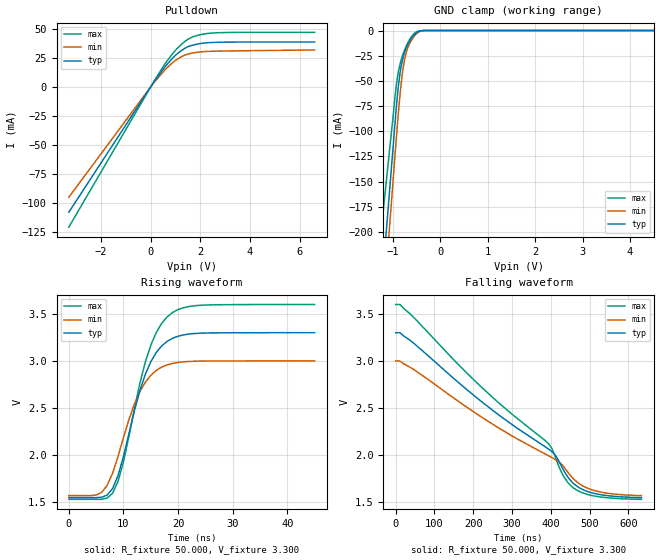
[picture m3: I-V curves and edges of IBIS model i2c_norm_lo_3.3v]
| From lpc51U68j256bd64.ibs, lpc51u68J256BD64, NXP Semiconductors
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[Model]   i2c_norm_lo_3.3v
Model_type I/O_open_drain
Vinl=8.000E-01
Vinh=2.000E+00
Vref=3.300E+00
Rref=1.000E+03
Cref=0.000E+00
Vmeas=1.650E+00
C_comp   1.270E-12   1.260E-12   1.280E-12
[Voltage Range]   3.300E+00   3.000E+00   3.600E+00
[POWER Clamp Reference]   3.300E+00   3.000E+00   3.600E+00
[GND Clamp Reference]   0.000E+00   0.000E+00   0.000E+00
[Pullup Reference]   3.300E+00   3.000E+00   3.600E+00
[Pulldown Reference]   0.000E+00   0.000E+00   0.000E+00
[Temperature Range]   25   105   -40
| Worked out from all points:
|   slope of the pulldown table from 0 to 0.495 V, typ, clamps not added: 33 ohm
|   GND clamp passes 1 mA (typ) near -0.46 V on its own axis
|   rising waveform, R_fixture 50.000, V_fixture 3.300: 20-80 % time 5.12ns typ, 5.13ns min, 5.08ns max; typ from 1.55 V to 3.3 V
|   falling waveform, R_fixture 50.000, V_fixture 3.300: 20-80 % time 313ns typ, 324ns min, 305ns max; typ from 3.3 V to 1.55 V
[GND Clamp]
-3.3V     -1.458A    -1.562A    -1.131A
-1.02V    -130mA     -163.9mA   -96.03mA
-940mV    -83.07mA   -114.7mA   -59.17mA
-880mV    -53.59mA   -79.56mA   -39.94mA
-820mV    -34.18mA   -50.5mA    -28.4mA
-780mV    -25.98mA   -36.17mA   -22.72mA
-720mV    -17.58mA   -22.11mA   -15.62mA
-660mV    -11.67mA   -14.14mA   -9.957mA
-560mV    -4.68mA    -6.191mA   -3.364mA
-480mV    -1.522mA   -2.335mA   -915uA
-340mV    0A         0A         0A
6.6V      0A         0A         0A
[Pulldown]
-3.3V     -108.3mA   -95.33mA   -121.2mA
160mV     5.143mA    4.418mA    5.829mA
580mV     17.51mA    14.82mA    20.06mA
840mV     23.85mA    20.1mA     27.52mA
1.04V     28.06mA    23.49mA    32.6mA
1.36V     33.07mA    27.32mA    38.93mA
1.68V     35.86mA    29.22mA    43.1mA
1.9V      37.05mA    29.92mA    44.55mA
2.58V     38.42mA    30.76mA    46.6mA
6.6V      38.69mA    31.86mA    47.08mA
[Rising Waveform]
R_fixture = 50.000
V_fixture = 3.300
V_fixture_min = 3.000
V_fixture_max = 3.600
|  time   V(typ)   V(min)   V(max)
0s        1.546V     1.568V     1.528V
6ns       1.55V      1.602V     1.528V
8ns       1.641V     1.804V     1.592V
10ns      1.982V     2.183V     1.924V
12ns      2.467V     2.54V      2.488V
15ns      2.99V      2.846V     3.166V
17ns      3.159V     2.934V     3.4V
19ns      3.241V     2.974V     3.515V
24ns      3.295V     2.998V     3.591V
45ns      3.3V       3V         3.6V
[Falling Waveform]
R_fixture = 50.000
V_fixture = 3.300
V_fixture_min = 3.000
V_fixture_max = 3.600
|  time   V(typ)   V(min)   V(max)
0s        3.3V       3V         3.6V
12ns      3.297V     2.995V     3.596V
44ns      3.197V     2.915V     3.473V
244ns     2.495V     2.343V     2.635V
393ns     2.066V     1.995V     2.124V
415ns     1.978V     1.943V     1.943V
432ns     1.846V     1.881V     1.78V
457ns     1.703V     1.753V     1.655V
515ns     1.589V     1.619V     1.562V
634ns     1.546V     1.568V     1.528V
[Ramp]
dV/dt_r   1.0522E+00/5.0520E-09   8.5491E-01/5.0710E-09   1.2498E+00/5.0520E-09
dV/dt_f   1.0522E+00/3.1298E-07   8.5491E-01/3.2391E-07   1.2498E+00/3.0505E-07
R_load = 50
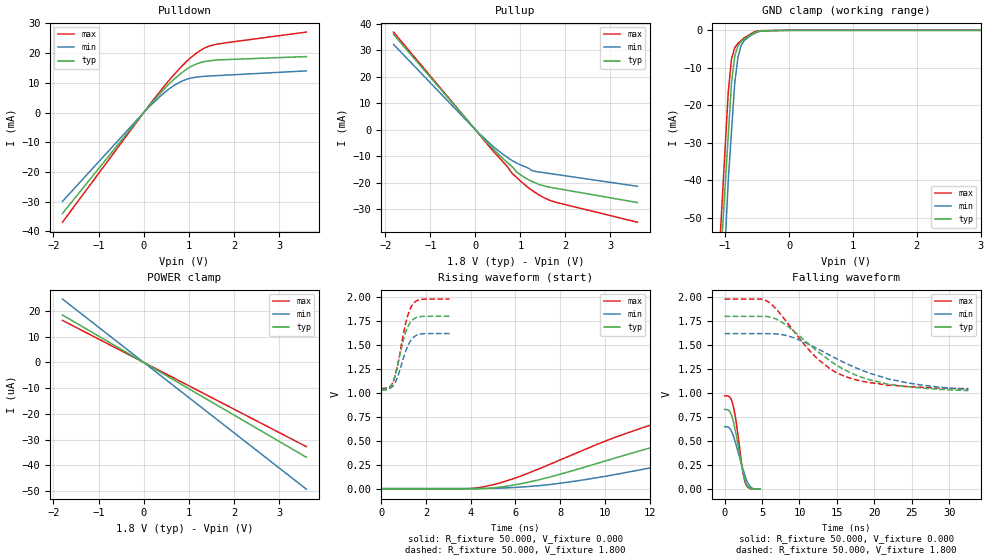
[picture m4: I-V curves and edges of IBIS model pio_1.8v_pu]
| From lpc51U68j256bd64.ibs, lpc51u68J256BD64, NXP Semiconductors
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[Model]   pio_1.8v_pu
Model_type I/O
Vinl=4.000E-01
Vinh=1.500E+00
Vref=0.000E+00
Rref=1.000E+06
Cref=2.000E-11
Vmeas=9.000E-01
C_comp   9.060E-12   8.700E-12   9.420E-12
[Voltage Range]   1.800E+00   1.620E+00   1.980E+00
[POWER Clamp Reference]   1.800E+00   1.620E+00   1.980E+00
[GND Clamp Reference]   0.000E+00   0.000E+00   0.000E+00
[Pullup Reference]   1.800E+00   1.620E+00   1.980E+00
[Pulldown Reference]   0.000E+00   0.000E+00   0.000E+00
[Temperature Range]   25   105   -40
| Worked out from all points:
|   slope of the pulldown table from 0 to 0.27 V, typ, clamps not added: 55.9 ohm
|   slope of the pullup table from 0 to 0.27 V, typ, clamps not added: 53.5 ohm
|   GND clamp passes 1 mA (typ) near -0.59 V on its own axis
|   rising waveform, R_fixture 50.000, V_fixture 0.000: 20-80 % time 8.49ns typ, 10.2ns min, 6.96ns max; typ from -0.006 V to 0.824 V
|   falling waveform, R_fixture 50.000, V_fixture 0.000: 20-80 % time 1.2ns typ, 1.45ns min, 1.03ns max; typ from 0.831 V to 0.001 V
|   rising waveform, R_fixture 50.000, V_fixture 1.800: 20-80 % time 492ps typ, 502ps min, 486ps max; typ from 1.03 V to 1.8 V
|   falling waveform, R_fixture 50.000, V_fixture 1.800: 20-80 % time 8.49ns typ, 10.1ns min, 6.71ns max; typ from 1.8 V to 1.03 V
[GND Clamp]
-1.8V     -263.7mA   -335.6mA   -275.8mA
-950mV    -27.75mA   -39.74mA   -16.17mA
-900mV    -13.87mA   -26.94mA   -7.61mA
-850mV    -6.971mA   -14.14mA   -4.632mA
-800mV    -4.156mA   -7.28mA    -3.484mA
-750mV    -2.988mA   -4.044mA   -2.731mA
-700mV    -2.361mA   -2.687mA   -1.978mA
-600mV    -1.106mA   -1.378mA   -966uA
-550mV    -718uA     -946.2uA   -460.3uA
-450mV    -144.5uA   -255.5uA   -88.61uA
0V        0A         0A         0A
3.6V      0A         0A         0A
[Power Clamp]
-1.8V     18.45uA    24.66uA    16.39uA
0V        0A         0A         0A
3.6V      -36.9uA    -49.32uA   -32.77uA
[Pullup]
-1.82V    35.96mA    32.21mA    36.85mA
80mV      -1.544mA   -1.344mA   -1.647mA
500mV     -9.045mA   -7.794mA   -9.994mA
700mV     -12.23mA   -10.32mA   -13.77mA
800mV     -13.69mA   -11.44mA   -16.11mA
940mV     -16.27mA   -12.77mA   -18.38mA
1.16V     -18.65mA   -14.36mA   -21.65mA
1.26V     -19.53mA   -15.44mA   -22.89mA
1.44V     -20.77mA   -16.02mA   -24.89mA
1.66V     -21.72mA   -16.55mA   -26.68mA
3.6V      -27.48mA   -21.34mA   -34.89mA
[Pulldown]
-1.8V     -34.01mA   -29.94mA   -36.95mA
0V        0A         0A         0A
380mV     6.716mA    5.665mA    7.485mA
600mV     10.22mA    8.397mA    11.57mA
840mV     13.38mA    10.54mA    15.59mA
1.02V     15.31mA    11.52mA    18.23mA
1.16V     16.32mA    11.92mA    19.92mA
1.38V     17.25mA    12.23mA    21.97mA
1.62V     17.72mA    12.43mA    23.02mA
3.6V      18.85mA    14.03mA    27.1mA
[Rising Waveform]
R_fixture = 50.000
V_fixture = 0.000
V_fixture_min = 0.000
V_fixture_max = 0.000
|  time   V(typ)   V(min)   V(max)
0s        -5.789mV   1.396mV    -4.844mV
3.7ns     -4.923mV   1.575mV    -2.372mV
4.95ns    6.383mV    3.245mV    37.73mV
7.05ns    91.82mV    30.65mV    206.2mV
11.75ns   407.3mV    203.7mV    641.5mV
13.6ns    519.6mV    286.3mV    761.3mV
15.5ns    613.2mV    365.4mV    841.4mV
20.9ns    764.1mV    538mV      935mV
25.8ns    810.2mV    622mV      959mV
30.1ns    823.9mV    651.5mV    967.2mV
[Falling Waveform]
R_fixture = 50.000
V_fixture = 0.000
V_fixture_min = 0.000
V_fixture_max = 0.000
|  time   V(typ)   V(min)   V(max)
0s        831.3mV    651.5mV    972.6mV
650ps     813mV      636.2mV    961.7mV
900ps     776.3mV    607.1mV    932mV
1.15ns    713.4mV    560.6mV    870.8mV
1.6ns     547.3mV    446.3mV    673.2mV
2.4ns     201.9mV    225.1mV    202.4mV
2.8ns     76.49mV    124.4mV    60.41mV
3.1ns     29.6mV     66.64mV    21.01mV
3.55ns    6.817mV    18.78mV    4.66mV
4.75ns    1.009mV    1.396mV    965.5uV
[Rising Waveform]
R_fixture = 50.000
V_fixture = 1.800
V_fixture_min = 1.620
V_fixture_max = 1.980
|  time   V(typ)   V(min)   V(max)
0s        1.028V     1.04V      1.048V
350ps     1.047V     1.046V     1.059V
550ps     1.131V     1.081V     1.128V
700ps     1.257V     1.15V      1.256V
1.05ns    1.603V     1.408V     1.686V
1.2ns     1.697V     1.498V     1.821V
1.4ns     1.764V     1.571V     1.924V
1.55ns    1.786V     1.598V     1.958V
1.75ns    1.797V     1.614V     1.975V
3.05ns    1.8V       1.62V      1.98V
[Falling Waveform]
R_fixture = 50.000
V_fixture = 1.800
V_fixture_min = 1.620
V_fixture_max = 1.980
|  time   V(typ)   V(min)   V(max)
0s        1.8V       1.62V      1.98V
4.75ns    1.8V       1.62V      1.98V
5.8ns     1.797V     1.619V     1.952V
8.15ns    1.713V     1.602V     1.756V
12.3ns    1.442V     1.468V     1.366V
14.15ns   1.333V     1.391V     1.25V
16.25ns   1.234V     1.309V     1.17V
21.75ns   1.095V     1.151V     1.083V
26.55ns   1.052V     1.082V     1.061V
32.55ns   1.028V     1.04V      1.048V
[Ramp]
dV/dt_r   4.9781E-01/8.4744E-09   3.9098E-01/1.0185E-08   5.8325E-01/6.9452E-09
dV/dt_f   4.6327E-01/8.4811E-09   3.4800E-01/1.0136E-08   5.5946E-01/6.7072E-09
R_load = 50
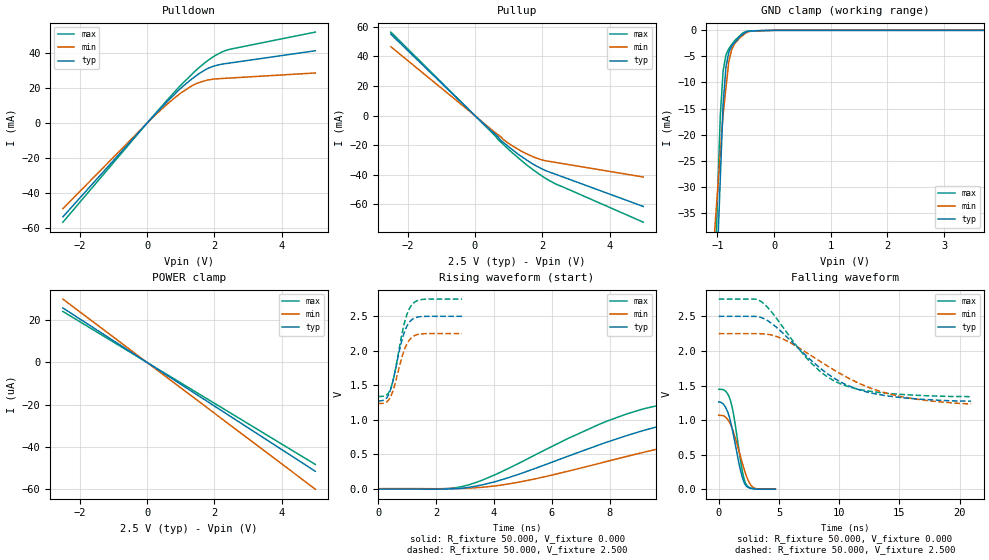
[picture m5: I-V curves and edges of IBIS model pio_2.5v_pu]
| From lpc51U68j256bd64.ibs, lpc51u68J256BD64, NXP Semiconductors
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[Model]   pio_2.5v_pu
Model_type I/O
Vinl=4.000E-01
Vinh=1.500E+00
Vref=0.000E+00
Rref=1.000E+06
Cref=2.000E-11
Vmeas=1.250E+00
C_comp   9.060E-12   8.700E-12   9.420E-12
[Voltage Range]   2.500E+00   2.250E+00   2.750E+00
[POWER Clamp Reference]   2.500E+00   2.250E+00   2.750E+00
[GND Clamp Reference]   0.000E+00   0.000E+00   0.000E+00
[Pullup Reference]   2.500E+00   2.250E+00   2.750E+00
[Pulldown Reference]   0.000E+00   0.000E+00   0.000E+00
[Temperature Range]   25   105   -40
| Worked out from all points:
|   slope of the pulldown table from 0 to 0.375 V, typ, clamps not added: 48.2 ohm
|   slope of the pullup table from 0 to 0.375 V, typ, clamps not added: 47.2 ohm
|   GND clamp passes 1 mA (typ) near -0.58 V on its own axis
|   rising waveform, R_fixture 50.000, V_fixture 0.000: 20-80 % time 5.59ns typ, 6.98ns min, 4.66ns max; typ from -0.006 V to 1.26 V
|   falling waveform, R_fixture 50.000, V_fixture 0.000: 20-80 % time 902ps typ, 1.09ns min, 781ps max; typ from 1.26 V to 0.001 V
|   rising waveform, R_fixture 50.000, V_fixture 2.500: 20-80 % time 408ps typ, 413ps min, 407ps max; typ from 1.27 V to 2.5 V
|   falling waveform, R_fixture 50.000, V_fixture 2.500: 20-80 % time 5.14ns typ, 6.37ns min, 4.26ns max; typ from 2.5 V to 1.27 V
[GND Clamp]
-2.5V     -475.7mA   -255.8mA   -509.6mA
-950mV    -28.56mA   -23.6mA    -16.48mA
-900mV    -14.13mA   -16.11mA   -7.789mA
-850mV    -7.08mA    -11.07mA   -4.709mA
-800mV    -4.224mA   -6.027mA   -3.542mA
-750mV    -3.043mA   -3.75mA    -2.78mA
-700mV    -2.406mA   -2.615mA   -2.018mA
-600mV    -1.132mA   -1.373mA   -993uA
-500mV    -345.9uA   -523.1uA   -221.8uA
-400mV    -135.5uA   -126.9uA   -93.31uA
0V        0A         0A         0A
5V        0A         0A         0A
[Power Clamp]
-2.5V     25.73uA    29.96uA    24.11uA
0V        0A         0A         0A
5V        -51.47uA   -59.93uA   -48.22uA
[Pullup]
-2.5V     55.03mA    46.51mA    56.39mA
0V        0A         0A         0A
560mV     -11.71mA   -10.66mA   -12.69mA
760mV     -16.48mA   -14.18mA   -17.72mA
1V        -20.97mA   -18.73mA   -22.83mA
1.42V     -28.23mA   -24.51mA   -31.07mA
1.96V     -35.62mA   -29.68mA   -40.25mA
2.38V     -39.45mA   -31.53mA   -45.93mA
5V        -61.32mA   -41.44mA   -71.95mA
[Pulldown]
-2.5V     -53.75mA   -49.06mA   -56.82mA
0V        0A         0A         0A
360mV     7.48mA     6.68mA     7.998mA
980mV     19.59mA    16.96mA    21.32mA
1.32V     25.16mA    21.25mA    27.81mA
1.54V     28.36mA    23.25mA    31.74mA
1.94V     32.45mA    25.18mA    37.76mA
2.36V     34.22mA    25.76mA    41.85mA
5V        41.54mA    28.79mA    52.24mA
[Rising Waveform]
R_fixture = 50.000
V_fixture = 0.000
V_fixture_min = 0.000
V_fixture_max = 0.000
|  time   V(typ)   V(min)   V(max)
0s        -5.765mV   1.234mV    -1.766mV
2.3ns     -4.275mV   975.2uV    -144.2uV
3.15ns    20.28mV    8.635mV    58.7mV
5ns       229.5mV    106.2mV    397.3mV
7.9ns     674.2mV    394.7mV    977.9mV
9.15ns    841.3mV    524.9mV    1.155V
10.4ns    976.6mV    646.1mV    1.265V
12.45ns   1.114V     811.6mV    1.354V
15.5ns    1.201V     959.5mV    1.409V
22.85ns   1.256V     1.07V      1.441V
[Falling Waveform]
R_fixture = 50.000
V_fixture = 0.000
V_fixture_min = 0.000
V_fixture_max = 0.000
|  time   V(typ)   V(min)   V(max)
0s        1.263V     1.07V      1.445V
550ps     1.19V      1.044V     1.421V
1ns       963.2mV    928.6mV    1.266V
1.3ns     715.9mV    783.8mV    1.011V
1.85ns    242.3mV    445.6mV    370.9mV
2.1ns     103.6mV    294.8mV    154.3mV
2.3ns     45.62mV    190.5mV    65.39mV
2.6ns     15.81mV    77.74mV    22.4mV
2.95ns    5.503mV    18.61mV    9.325mV
4.7ns     1.266mV    1.234mV    1.248mV
[Rising Waveform]
R_fixture = 50.000
V_fixture = 2.500
V_fixture_min = 2.250
V_fixture_max = 2.750
|  time   V(typ)   V(min)   V(max)
0s        1.274V     1.235V     1.337V
250ps     1.298V     1.248V     1.349V
350ps     1.353V     1.28V      1.385V
450ps     1.465V     1.352V     1.475V
600ps     1.734V     1.549V     1.738V
850ps     2.199V     1.947V     2.302V
1ns       2.363V     2.105V     2.534V
1.2ns     2.461V     2.206V     2.684V
1.55ns    2.498V     2.247V     2.745V
2.9ns     2.5V       2.25V      2.75V
[Falling Waveform]
R_fixture = 50.000
V_fixture = 2.500
V_fixture_min = 2.250
V_fixture_max = 2.750
|  time   V(typ)   V(min)   V(max)
0s        2.5V       2.25V      2.75V
2.95ns    2.499V     2.25V      2.749V
3.55ns    2.481V     2.248V     2.71V
5.25ns    2.27V      2.178V     2.363V
7.7ns     1.859V     1.929V     1.82V
8.95ns    1.68V      1.79V      1.634V
10.25ns   1.539V     1.655V     1.515V
12.25ns   1.409V     1.486V     1.425V
14.65ns   1.335V     1.357V     1.377V
20.95ns   1.274V     1.235V     1.337V
[Ramp]
dV/dt_r   7.5711E-01/5.5865E-09   6.3920E-01/6.9663E-09   8.6573E-01/4.6619E-09
dV/dt_f   7.3584E-01/5.1385E-09   6.0892E-01/6.3638E-09   8.4764E-01/4.2601E-09
R_load = 50
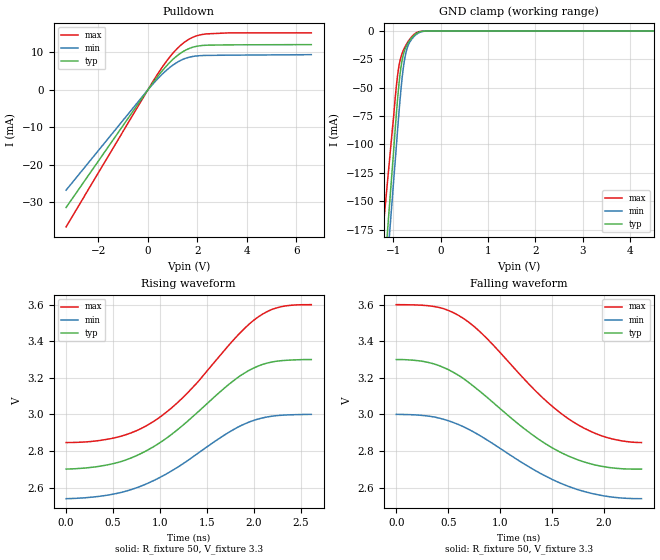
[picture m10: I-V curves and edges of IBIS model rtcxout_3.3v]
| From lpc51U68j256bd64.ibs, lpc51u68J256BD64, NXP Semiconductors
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[Model]   rtcxout_3.3v
Model_type Open_drain
Vref=3.300E+00
Rref=1.000E+03
Cref=0.000E+00
Vmeas=1.650E+00
C_comp   1.410E-12   1.370E-12   1.450E-12
[Voltage Range]   3.300E+00   3.000E+00   3.600E+00
[POWER Clamp Reference]   3.300E+00   3.000E+00   3.600E+00
[GND Clamp Reference]   0.000E+00   0.000E+00   0.000E+00
[Pullup Reference]   3.300E+00   3.000E+00   3.600E+00
[Pulldown Reference]   0.000E+00   0.000E+00   0.000E+00
[Temperature Range]   25   85   -40
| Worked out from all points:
|   slope of the pulldown table from 0 to 0.495 V, typ, clamps not added: 113 ohm
|   GND clamp passes 1 mA (typ) near -0.46 V on its own axis
|   rising waveform, R_fixture 50, V_fixture 3.3: 20-80 % time 851ps typ, 848ps min, 829ps max; typ from 2.7 V to 3.3 V
|   falling waveform, R_fixture 50, V_fixture 3.3: 20-80 % time 806ps typ, 819ps min, 795ps max; typ from 3.3 V to 2.7 V
[GND Clamp]
-3.3V     -1.375A    -1.371A    -1.106A
-1.02V    -118.2mA   -144.9mA   -85.2mA
-940mV    -73.79mA   -101.9mA   -48.86mA
-900mV    -53.84mA   -80.23mA   -34.95mA
-860mV    -37.67mA   -59.97mA   -25.8mA
-840mV    -31.36mA   -50.76mA   -22.62mA
-780mV    -19.01mA   -28.85mA   -15.97mA
-740mV    -14.36mA   -19.6mA    -12.67mA
-680mV    -9.669mA   -11.74mA   -8.538mA
-500mV    -1.745mA   -2.422mA   -1.162mA
-260mV    0A         0A         0A
6.6V      0A         0A         0A
[Pulldown]
-3.3V     -31.36mA   -26.74mA   -36.52mA
0V        0A         0A         0A
360mV     3.254mA    2.698mA    3.852mA
580mV     5.099mA    4.199mA    6.066mA
1V        8.077mA    6.56mA     9.704mA
1.46V     10.38mA    8.272mA    12.63mA
1.7V      11.12mA    8.765mA    13.65mA
1.94V     11.59mA    9.039mA    14.35mA
2.38V     11.93mA    9.205mA    14.94mA
3.3V      12.02mA    9.266mA    15.22mA
6.6V      12.08mA    9.397mA    15.22mA
[Rising Waveform]
R_fixture = 50
V_fixture = 3.3
V_fixture_min = 3
V_fixture_max = 3.6
0s        2.701V     2.539V     2.846V
490ps     2.73V      2.563V     2.869V
690ps     2.761V     2.588V     2.898V
860ps     2.803V     2.621V     2.939V
1.05ns    2.863V     2.669V     3.005V
1.25ns    2.943V     2.732V     3.095V
1.75ns    3.171V     2.907V     3.389V
2.02ns    3.259V     2.971V     3.524V
2.27ns    3.293V     2.994V     3.586V
2.61ns    3.3V       3V         3.6V
[Falling Waveform]
R_fixture = 50
V_fixture = 3.3
V_fixture_min = 3
V_fixture_max = 3.6
0s        3.3V       3V         3.6V
340ps     3.28V      2.988V     3.592V
590ps     3.217V     2.947V     3.544V
810ps     3.123V     2.882V     3.45V
1.31ns    2.889V     2.702V     3.146V
1.65ns    2.774V     2.608V     2.979V
1.81ns    2.74V      2.578V     2.924V
1.99ns    2.715V     2.555V     2.88V
2.17ns    2.703V     2.543V     2.855V
2.36ns    2.701V     2.539V     2.846V
[Ramp]
dV/dt_r   3.5949E-01/8.4980E-10   2.7655E-01/8.4680E-10   4.5233E-01/8.2910E-10
dV/dt_f   3.5949E-01/8.0641E-10   2.7655E-01/8.1844E-10   4.5233E-01/7.9410E-10
R_load = 50
